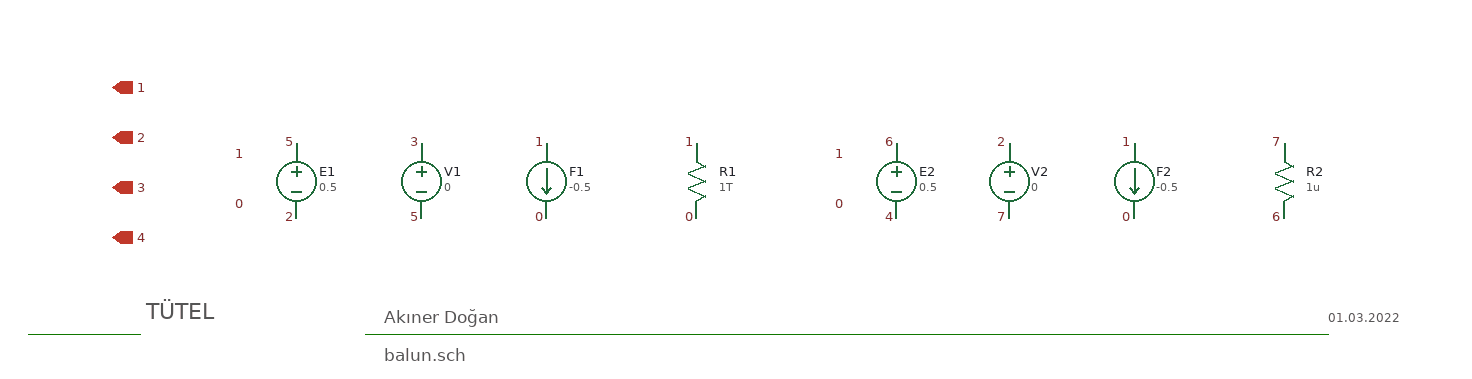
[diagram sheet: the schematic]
v {xschem version=3.0.0 file_version=1.2 }
G {}
K {}
V {}
S {}
E {}
L 4 -0 0 90 0 {}
L 4 430 0 1040 0 {}
L 4 280 -0 430 0 {}
L 4 270 -0 280 0 {}
T {balun.sch} 285 5 0 0 0.4 0.4 {}
T {Akıner Doğan} 285 -25 0 0 0.4 0.4 {}
T {01.03.2022} 1040 -25 0 1 0.3 0.3 {}
T {TÜTEL} 95 -30 0 0 1 1 {}
C {devices/vcvs.sym} 215 -122.5 0 0 {name=E1 value=0.5}
C {devices/vsource.sym} 315 -122.5 0 0 {name=V1 value=0}
C {devices/cccs.sym} 415 -122.5 0 0 {name=F1 vnam=V1 value=-0.5}
C {devices/lab_pin.sym} 215 -152.5 1 0 {name=l1 sig_type=std_logic lab=5}
C {devices/res.sym} 535 -122.5 0 0 {name=R1
value=1T
device=resistor}
C {devices/vcvs.sym} 695 -122.5 0 0 {name=E2 value=0.5}
C {devices/vsource.sym} 785 -122.5 0 0 {name=V2 value=0}
C {devices/cccs.sym} 885 -122.5 0 0 {name=F2 vnam=V2 value=-0.5}
C {devices/res.sym} 1005 -122.5 0 0 {name=R2
value=1u
footprint=1206
device=resistor
m=1}
C {devices/lab_pin.sym} 175 -142.5 0 0 {name=l2 sig_type=std_logic lab=1}
C {devices/lab_pin.sym} 175 -102.5 0 0 {name=l3 sig_type=std_logic lab=0}
C {devices/lab_pin.sym} 655 -142.5 0 0 {name=l4 sig_type=std_logic lab=1}
C {devices/lab_pin.sym} 655 -102.5 0 0 {name=l5 sig_type=std_logic lab=0}
C {devices/lab_pin.sym} 315 -152.5 1 0 {name=l6 sig_type=std_logic lab=3}
C {devices/lab_pin.sym} 415 -152.5 1 0 {name=l7 sig_type=std_logic lab=1}
C {devices/lab_pin.sym} 535 -152.5 1 0 {name=l8 sig_type=std_logic lab=1}
C {devices/lab_pin.sym} 695 -152.5 1 0 {name=l9 sig_type=std_logic lab=6}
C {devices/lab_pin.sym} 785 -152.5 1 0 {name=l10 sig_type=std_logic lab=2}
C {devices/lab_pin.sym} 885 -152.5 1 0 {name=l11 sig_type=std_logic lab=1}
C {devices/lab_pin.sym} 1005 -152.5 1 0 {name=l12 sig_type=std_logic lab=7}
C {devices/lab_pin.sym} 215 -92.5 1 1 {name=l14 sig_type=std_logic lab=2}
C {devices/lab_pin.sym} 315 -92.5 1 1 {name=l15 sig_type=std_logic lab=5}
C {devices/lab_pin.sym} 415 -92.5 1 1 {name=l16 sig_type=std_logic lab=0}
C {devices/lab_pin.sym} 535 -92.5 1 1 {name=l17 sig_type=std_logic lab=0}
C {devices/lab_pin.sym} 695 -92.5 1 1 {name=l18 sig_type=std_logic lab=4}
C {devices/lab_pin.sym} 785 -92.5 1 1 {name=l19 sig_type=std_logic lab=7}
C {devices/lab_pin.sym} 885 -92.5 1 1 {name=l20 sig_type=std_logic lab=0}
C {devices/lab_pin.sym} 1005 -92.5 1 1 {name=l21 sig_type=std_logic lab=6}
C {devices/iopin.sym} 67.5 -197.5 0 1 {name=p1 lab=1}
C {devices/iopin.sym} 67.5 -157.5 0 1 {name=p2 lab=2}
C {devices/iopin.sym} 67.5 -117.5 0 1 {name=p3 lab=3}
C {devices/iopin.sym} 67.5 -77.5 0 1 {name=p4 lab=4}
